One B-rep face of a CAD part: STEP entity #614.
In plain terms, the planar face has unit normal (-1, 0, 0).
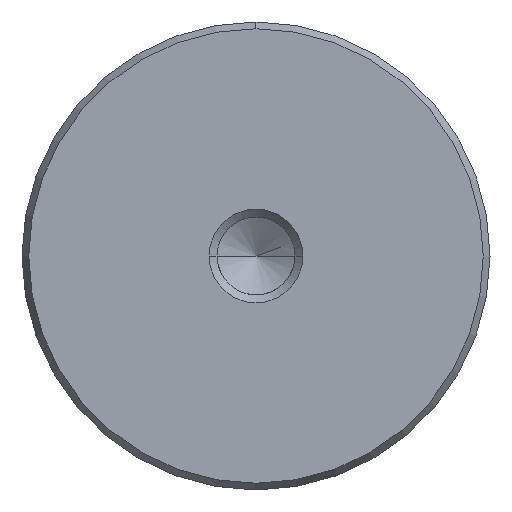
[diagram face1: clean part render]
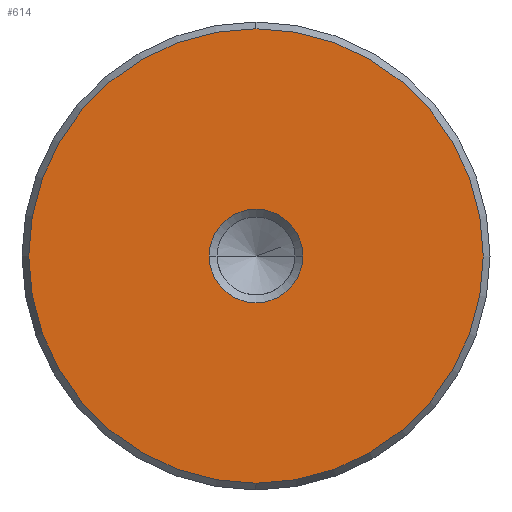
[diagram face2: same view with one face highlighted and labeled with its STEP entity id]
Its self-contained STEP definition (entity closure, numbers rounded to 3 decimals):
#528=CARTESIAN_POINT('Vertex',(0.,0.,-19.423)) ;
#531=CARTESIAN_POINT('Axis2P3D Location',(0.,0.,0.)) ;
#535=CARTESIAN_POINT('Vertex',(0.,19.423,0.)) ;
#538=CARTESIAN_POINT('Axis2P3D Location',(0.,0.,0.)) ;
#542=CARTESIAN_POINT('Vertex',(0.,0.,19.423)) ;
#564=CARTESIAN_POINT('Axis2P3D Location',(0.,0.,0.)) ;
#568=CARTESIAN_POINT('Vertex',(0.,-19.423,0.)) ;
#571=CARTESIAN_POINT('Axis2P3D Location',(0.,0.,0.)) ;
#585=CARTESIAN_POINT('Axis2P3D Location',(0.,0.,0.)) ;
#596=CARTESIAN_POINT('Axis2P3D Location',(0.,0.,0.)) ;
#600=CARTESIAN_POINT('Vertex',(0.,4.,0.)) ;
#602=CARTESIAN_POINT('Vertex',(0.,-4.,0.)) ;
#605=CARTESIAN_POINT('Axis2P3D Location',(0.,0.,0.)) ;
#532=DIRECTION('Axis2P3D Direction',(1.,0.,-0.)) ;
#539=DIRECTION('Axis2P3D Direction',(1.,0.,-0.)) ;
#565=DIRECTION('Axis2P3D Direction',(1.,0.,-0.)) ;
#572=DIRECTION('Axis2P3D Direction',(1.,0.,-0.)) ;
#586=DIRECTION('Axis2P3D Direction',(1.,0.,-0.)) ;
#587=DIRECTION('Axis2P3D XDirection',(-0.,0.,-1.)) ;
#597=DIRECTION('Axis2P3D Direction',(1.,0.,-0.)) ;
#606=DIRECTION('Axis2P3D Direction',(1.,0.,-0.)) ;
#533=AXIS2_PLACEMENT_3D('Circle Axis2P3D',#531,#532,$) ;
#540=AXIS2_PLACEMENT_3D('Circle Axis2P3D',#538,#539,$) ;
#566=AXIS2_PLACEMENT_3D('Circle Axis2P3D',#564,#565,$) ;
#573=AXIS2_PLACEMENT_3D('Circle Axis2P3D',#571,#572,$) ;
#588=AXIS2_PLACEMENT_3D('Plane Axis2P3D',#585,#586,#587) ;
#598=AXIS2_PLACEMENT_3D('Circle Axis2P3D',#596,#597,$) ;
#607=AXIS2_PLACEMENT_3D('Circle Axis2P3D',#605,#606,$) ;
#591=ORIENTED_EDGE('',*,*,#537,.F.) ;
#592=ORIENTED_EDGE('',*,*,#575,.F.) ;
#593=ORIENTED_EDGE('',*,*,#570,.F.) ;
#594=ORIENTED_EDGE('',*,*,#544,.F.) ;
#611=ORIENTED_EDGE('',*,*,#604,.T.) ;
#612=ORIENTED_EDGE('',*,*,#609,.T.) ;
#613=FACE_BOUND('',#610,.T.) ;
#614=ADVANCED_FACE('720-40x224',(#595,#613),#589,.F.) ;
#534=CIRCLE('generated circle',#533,19.423) ;
#541=CIRCLE('generated circle',#540,19.423) ;
#567=CIRCLE('generated circle',#566,19.423) ;
#574=CIRCLE('generated circle',#573,19.423) ;
#599=CIRCLE('generated circle',#598,4.) ;
#608=CIRCLE('generated circle',#607,4.) ;
#537=EDGE_CURVE('',#529,#536,#534,.T.) ;
#544=EDGE_CURVE('',#536,#543,#541,.T.) ;
#570=EDGE_CURVE('',#543,#569,#567,.T.) ;
#575=EDGE_CURVE('',#569,#529,#574,.T.) ;
#604=EDGE_CURVE('',#601,#603,#599,.T.) ;
#609=EDGE_CURVE('',#603,#601,#608,.T.) ;
#590=EDGE_LOOP('',(#591,#592,#593,#594)) ;
#610=EDGE_LOOP('',(#611,#612)) ;
#595=FACE_OUTER_BOUND('',#590,.T.) ;
#589=PLANE('Plane',#588) ;
#529=VERTEX_POINT('',#528) ;
#536=VERTEX_POINT('',#535) ;
#543=VERTEX_POINT('',#542) ;
#569=VERTEX_POINT('',#568) ;
#601=VERTEX_POINT('',#600) ;
#603=VERTEX_POINT('',#602) ;
